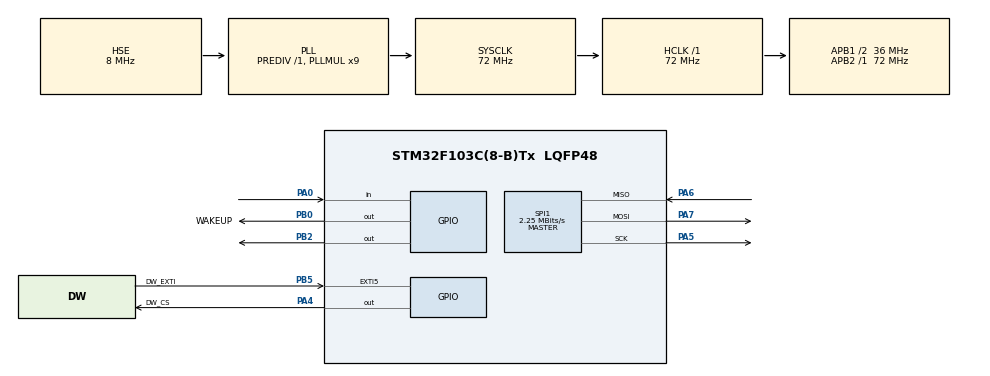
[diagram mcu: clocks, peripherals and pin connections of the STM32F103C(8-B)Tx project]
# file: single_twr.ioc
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Mcu.Family=STM32F1
Mcu.Name=STM32F103C(8-B)Tx
Mcu.Package=LQFP48
NVIC.PriorityGroup=NVIC_PRIORITYGROUP_4
PA0-WKUP.Signal=GPIO_Input
PA13.Mode=Serial_Wire
PA13.Signal=SYS_JTMS-SWDIO
PA14.Mode=Serial_Wire
PA14.Signal=SYS_JTCK-SWCLK
PA4.GPIO_Label=DW_CS
PA4.GPIO_ModeDefaultOutputPP=GPIO_MODE_OUTPUT_PP
PA4.GPIO_Speed=GPIO_SPEED_FREQ_HIGH
PA4.Signal=GPIO_Output
PA5.Mode=Full_Duplex_Master
PA5.Signal=SPI1_SCK
PA6.Mode=Full_Duplex_Master
PA6.Signal=SPI1_MISO
PA7.Mode=Full_Duplex_Master
PA7.Signal=SPI1_MOSI
PB0.GPIO_Label=WAKEUP
PB0.GPIO_ModeDefaultOutputPP=GPIO_MODE_OUTPUT_OD
PB0.GPIO_PuPd=GPIO_NOPULL
PB0.Signal=GPIO_Output
PB2.Signal=GPIO_Output
PB5.GPIO_Label=DW_EXTI
PB5.GPIO_PuPd=GPIO_PULLDOWN
PB5.Signal=GPXTI5
PD0-OSC_IN.Mode=HSE-External-Oscillator
PD0-OSC_IN.Signal=RCC_OSC_IN
PD1-OSC_OUT.Mode=HSE-External-Oscillator
PD1-OSC_OUT.Signal=RCC_OSC_OUT
ProjectManager.HeapSize=0x200
ProjectManager.StackSize=0x400
ProjectManager.TargetToolchain=STM32CubeIDE
RCC.AHBFreq_Value=72000000
RCC.APB1CLKDivider=RCC_HCLK_DIV2
RCC.APB1Freq_Value=36000000
RCC.APB1TimFreq_Value=72000000
RCC.APB2Freq_Value=72000000
RCC.APB2TimFreq_Value=72000000
RCC.HCLKFreq_Value=72000000
RCC.PLLMUL=RCC_PLL_MUL9
RCC.PLLSourceVirtual=RCC_PLLSOURCE_HSE
RCC.SYSCLKFreq_VALUE=72000000
RCC.SYSCLKSource=RCC_SYSCLKSOURCE_PLLCLK
RCC.USBFreq_Value=72000000
SPI1.BaudRatePrescaler=SPI_BAUDRATEPRESCALER_32
SPI1.CalculateBaudRate=2.25 MBits/s
SPI1.Direction=SPI_DIRECTION_2LINES
SPI1.Mode=SPI_MODE_MASTER
SPI1.VirtualType=VM_MASTER
TIM1.Period=49999
TIM1.Prescaler=143
VP_TIM1_VS_ClockSourceINT.Mode=Internal
board=custom

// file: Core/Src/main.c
/* USER CODE BEGIN Header */
/**
  ******************************************************************************
  * @file           : main.c
  * @brief          : Main program body
  ******************************************************************************
  * @attention
  *
  * Copyright (c) 2025 STMicroelectronics.
  * All rights reserved.
  *
  * This software is licensed under terms that can be found in the LICENSE file
  * in the root directory of this software component.
  * If no LICENSE file comes with this software, it is provided AS-IS.
  *
  ******************************************************************************
  */
/* USER CODE END Header */
#include "main.h"
#include "uwb.h"
#include "app_init.h"
#include "sleep.h"
#include "deca_device_api.h"

SPI_HandleTypeDef hspi1;

TIM_HandleTypeDef htim1;

void SystemClock_Config(void);
static void MX_GPIO_Init(void);
static void MX_SPI1_Init(void);
static void MX_TIM1_Init(void);

/* USER CODE BEGIN 0 */
twr_timestamps_t ts;
double tof, distance;
char dist_str[16];
uint32_t frame_seq_nb=0;

/* USER CODE END 0 */

int main(void)
{

  /* MCU Configuration--------------------------------------------------------*/

  /* Reset of all peripherals, Initializes the Flash interface and the Systick. */
  HAL_Init();

  /* Configure the system clock */
  SystemClock_Config();

  /* Initialize all configured peripherals */
  MX_GPIO_Init();
  MX_SPI1_Init();
  MX_TIM1_Init();
  /* USER CODE BEGIN 2 */
  UWB_Init();

  /* USER CODE END 2 */

  /* Infinite loop */
  while (1)
  {

    /* USER CODE BEGIN 3 */
	  ts.poll_tx_ts = send_poll_get_tx_timestamp(tx_poll_msg, 11);
	  // timeout 1000 μs (có thể điều chỉnh)
	   if(receive_response(&ts))
	          {
	              tof = calculate_tof(&ts);
	              distance = calculate_distance(tof);
	          }
	          deca_sleep(100);
	          frame_seq_nb++; // tăng số thứ tự frame

  }
  /* USER CODE END 3 */
}

void SystemClock_Config(void)
{
  RCC_OscInitTypeDef RCC_OscInitStruct = {0};
  RCC_ClkInitTypeDef RCC_ClkInitStruct = {0};

  /** Initializes the RCC Oscillators according to the specified parameters
  * in the RCC_OscInitTypeDef structure.
  */
  RCC_OscInitStruct.OscillatorType = RCC_OSCILLATORTYPE_HSE;
  RCC_OscInitStruct.HSEState = RCC_HSE_ON;
  RCC_OscInitStruct.HSEPredivValue = RCC_HSE_PREDIV_DIV1;
  RCC_OscInitStruct.HSIState = RCC_HSI_ON;
  RCC_OscInitStruct.PLL.PLLState = RCC_PLL_ON;
  RCC_OscInitStruct.PLL.PLLSource = RCC_PLLSOURCE_HSE;
  RCC_OscInitStruct.PLL.PLLMUL = RCC_PLL_MUL9;
  if (HAL_RCC_OscConfig(&RCC_OscInitStruct) != HAL_OK)
  {
    Error_Handler();
  }

  /** Initializes the CPU, AHB and APB buses clocks
  */
  RCC_ClkInitStruct.ClockType = RCC_CLOCKTYPE_HCLK|RCC_CLOCKTYPE_SYSCLK
                              |RCC_CLOCKTYPE_PCLK1|RCC_CLOCKTYPE_PCLK2;
  RCC_ClkInitStruct.SYSCLKSource = RCC_SYSCLKSOURCE_PLLCLK;
  RCC_ClkInitStruct.AHBCLKDivider = RCC_SYSCLK_DIV1;
  RCC_ClkInitStruct.APB1CLKDivider = RCC_HCLK_DIV2;
  RCC_ClkInitStruct.APB2CLKDivider = RCC_HCLK_DIV1;

  if (HAL_RCC_ClockConfig(&RCC_ClkInitStruct, FLASH_LATENCY_2) != HAL_OK)
  {
    Error_Handler();
  }
}

static void MX_SPI1_Init(void)
{

  /* SPI1 parameter configuration*/
  hspi1.Instance = SPI1;
  hspi1.Init.Mode = SPI_MODE_MASTER;
  hspi1.Init.Direction = SPI_DIRECTION_2LINES;
  hspi1.Init.DataSize = SPI_DATASIZE_8BIT;
  hspi1.Init.CLKPolarity = SPI_POLARITY_LOW;
  hspi1.Init.CLKPhase = SPI_PHASE_1EDGE;
  hspi1.Init.NSS = SPI_NSS_SOFT;
  hspi1.Init.BaudRatePrescaler = SPI_BAUDRATEPRESCALER_32;
  hspi1.Init.FirstBit = SPI_FIRSTBIT_MSB;
  hspi1.Init.TIMode = SPI_TIMODE_DISABLE;
  hspi1.Init.CRCCalculation = SPI_CRCCALCULATION_DISABLE;
  hspi1.Init.CRCPolynomial = 10;
  if (HAL_SPI_Init(&hspi1) != HAL_OK)
  {
    Error_Handler();
  }

}

static void MX_TIM1_Init(void)
{

  TIM_ClockConfigTypeDef sClockSourceConfig = {0};
  TIM_MasterConfigTypeDef sMasterConfig = {0};

  htim1.Instance = TIM1;
  htim1.Init.Prescaler = 143;
  htim1.Init.CounterMode = TIM_COUNTERMODE_UP;
  htim1.Init.Period = 49999;
  htim1.Init.ClockDivision = TIM_CLOCKDIVISION_DIV1;
  htim1.Init.RepetitionCounter = 0;
  htim1.Init.AutoReloadPreload = TIM_AUTORELOAD_PRELOAD_DISABLE;
  if (HAL_TIM_Base_Init(&htim1) != HAL_OK)
  {
    Error_Handler();
  }
  sClockSourceConfig.ClockSource = TIM_CLOCKSOURCE_INTERNAL;
  if (HAL_TIM_ConfigClockSource(&htim1, &sClockSourceConfig) != HAL_OK)
  {
    Error_Handler();
  }
  sMasterConfig.MasterOutputTrigger = TIM_TRGO_RESET;
  sMasterConfig.MasterSlaveMode = TIM_MASTERSLAVEMODE_DISABLE;
  if (HAL_TIMEx_MasterConfigSynchronization(&htim1, &sMasterConfig) != HAL_OK)
  {
    Error_Handler();
  }

}

static void MX_GPIO_Init(void)
{
  GPIO_InitTypeDef GPIO_InitStruct = {0};

  /* GPIO Ports Clock Enable */
  __HAL_RCC_GPIOD_CLK_ENABLE();
  __HAL_RCC_GPIOA_CLK_ENABLE();
  __HAL_RCC_GPIOB_CLK_ENABLE();

  /*Configure GPIO pin Output Level */
  HAL_GPIO_WritePin(DW_NSS_GPIO_Port, DW_NSS_Pin, GPIO_PIN_RESET);

  /*Configure GPIO pin Output Level */
  HAL_GPIO_WritePin(GPIOB, WAKEUP_Pin|GPIO_PIN_2, GPIO_PIN_RESET);

  /*Configure GPIO pin : PA0 */
  GPIO_InitStruct.Pin = GPIO_PIN_0;
  GPIO_InitStruct.Mode = GPIO_MODE_INPUT;
  GPIO_InitStruct.Pull = GPIO_NOPULL;
  HAL_GPIO_Init(GPIOA, &GPIO_InitStruct);

  /*Configure GPIO pin : DW_CS_Pin */
  GPIO_InitStruct.Pin = DW_NSS_Pin;
  GPIO_InitStruct.Mode = GPIO_MODE_OUTPUT_PP;
  GPIO_InitStruct.Pull = GPIO_NOPULL;
  GPIO_InitStruct.Speed = GPIO_SPEED_FREQ_HIGH;
  HAL_GPIO_Init(DW_NSS_GPIO_Port, &GPIO_InitStruct);

  /*Configure GPIO pin : WAKEUP_Pin */
  GPIO_InitStruct.Pin = WAKEUP_Pin;
  GPIO_InitStruct.Mode = GPIO_MODE_OUTPUT_OD;
  GPIO_InitStruct.Pull = GPIO_NOPULL;
  GPIO_InitStruct.Speed = GPIO_SPEED_FREQ_LOW;
  HAL_GPIO_Init(WAKEUP_GPIO_Port, &GPIO_InitStruct);

  /*Configure GPIO pin : PB2 */
  GPIO_InitStruct.Pin = GPIO_PIN_2;
  GPIO_InitStruct.Mode = GPIO_MODE_OUTPUT_PP;
  GPIO_InitStruct.Pull = GPIO_NOPULL;
  GPIO_InitStruct.Speed = GPIO_SPEED_FREQ_LOW;
  HAL_GPIO_Init(GPIOB, &GPIO_InitStruct);

  /*Configure GPIO pin : DW_EXTI_Pin */
  GPIO_InitStruct.Pin = DW_IRQn_Pin;
  GPIO_InitStruct.Mode = GPIO_MODE_IT_RISING;
  GPIO_InitStruct.Pull = GPIO_PULLDOWN;
  HAL_GPIO_Init(DW_IRQn_GPIO_Port, &GPIO_InitStruct);

}

void Error_Handler(void)
{
  __disable_irq();
  while (1)
  {
  }
}
